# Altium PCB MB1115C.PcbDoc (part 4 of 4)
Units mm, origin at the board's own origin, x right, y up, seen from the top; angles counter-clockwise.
Board outline 66 x 97 mm, 2 copper layers (TOP, Bottom), stack 1.535 mm thick; 198 components, 186 nets, 760 pads, 493 vias.

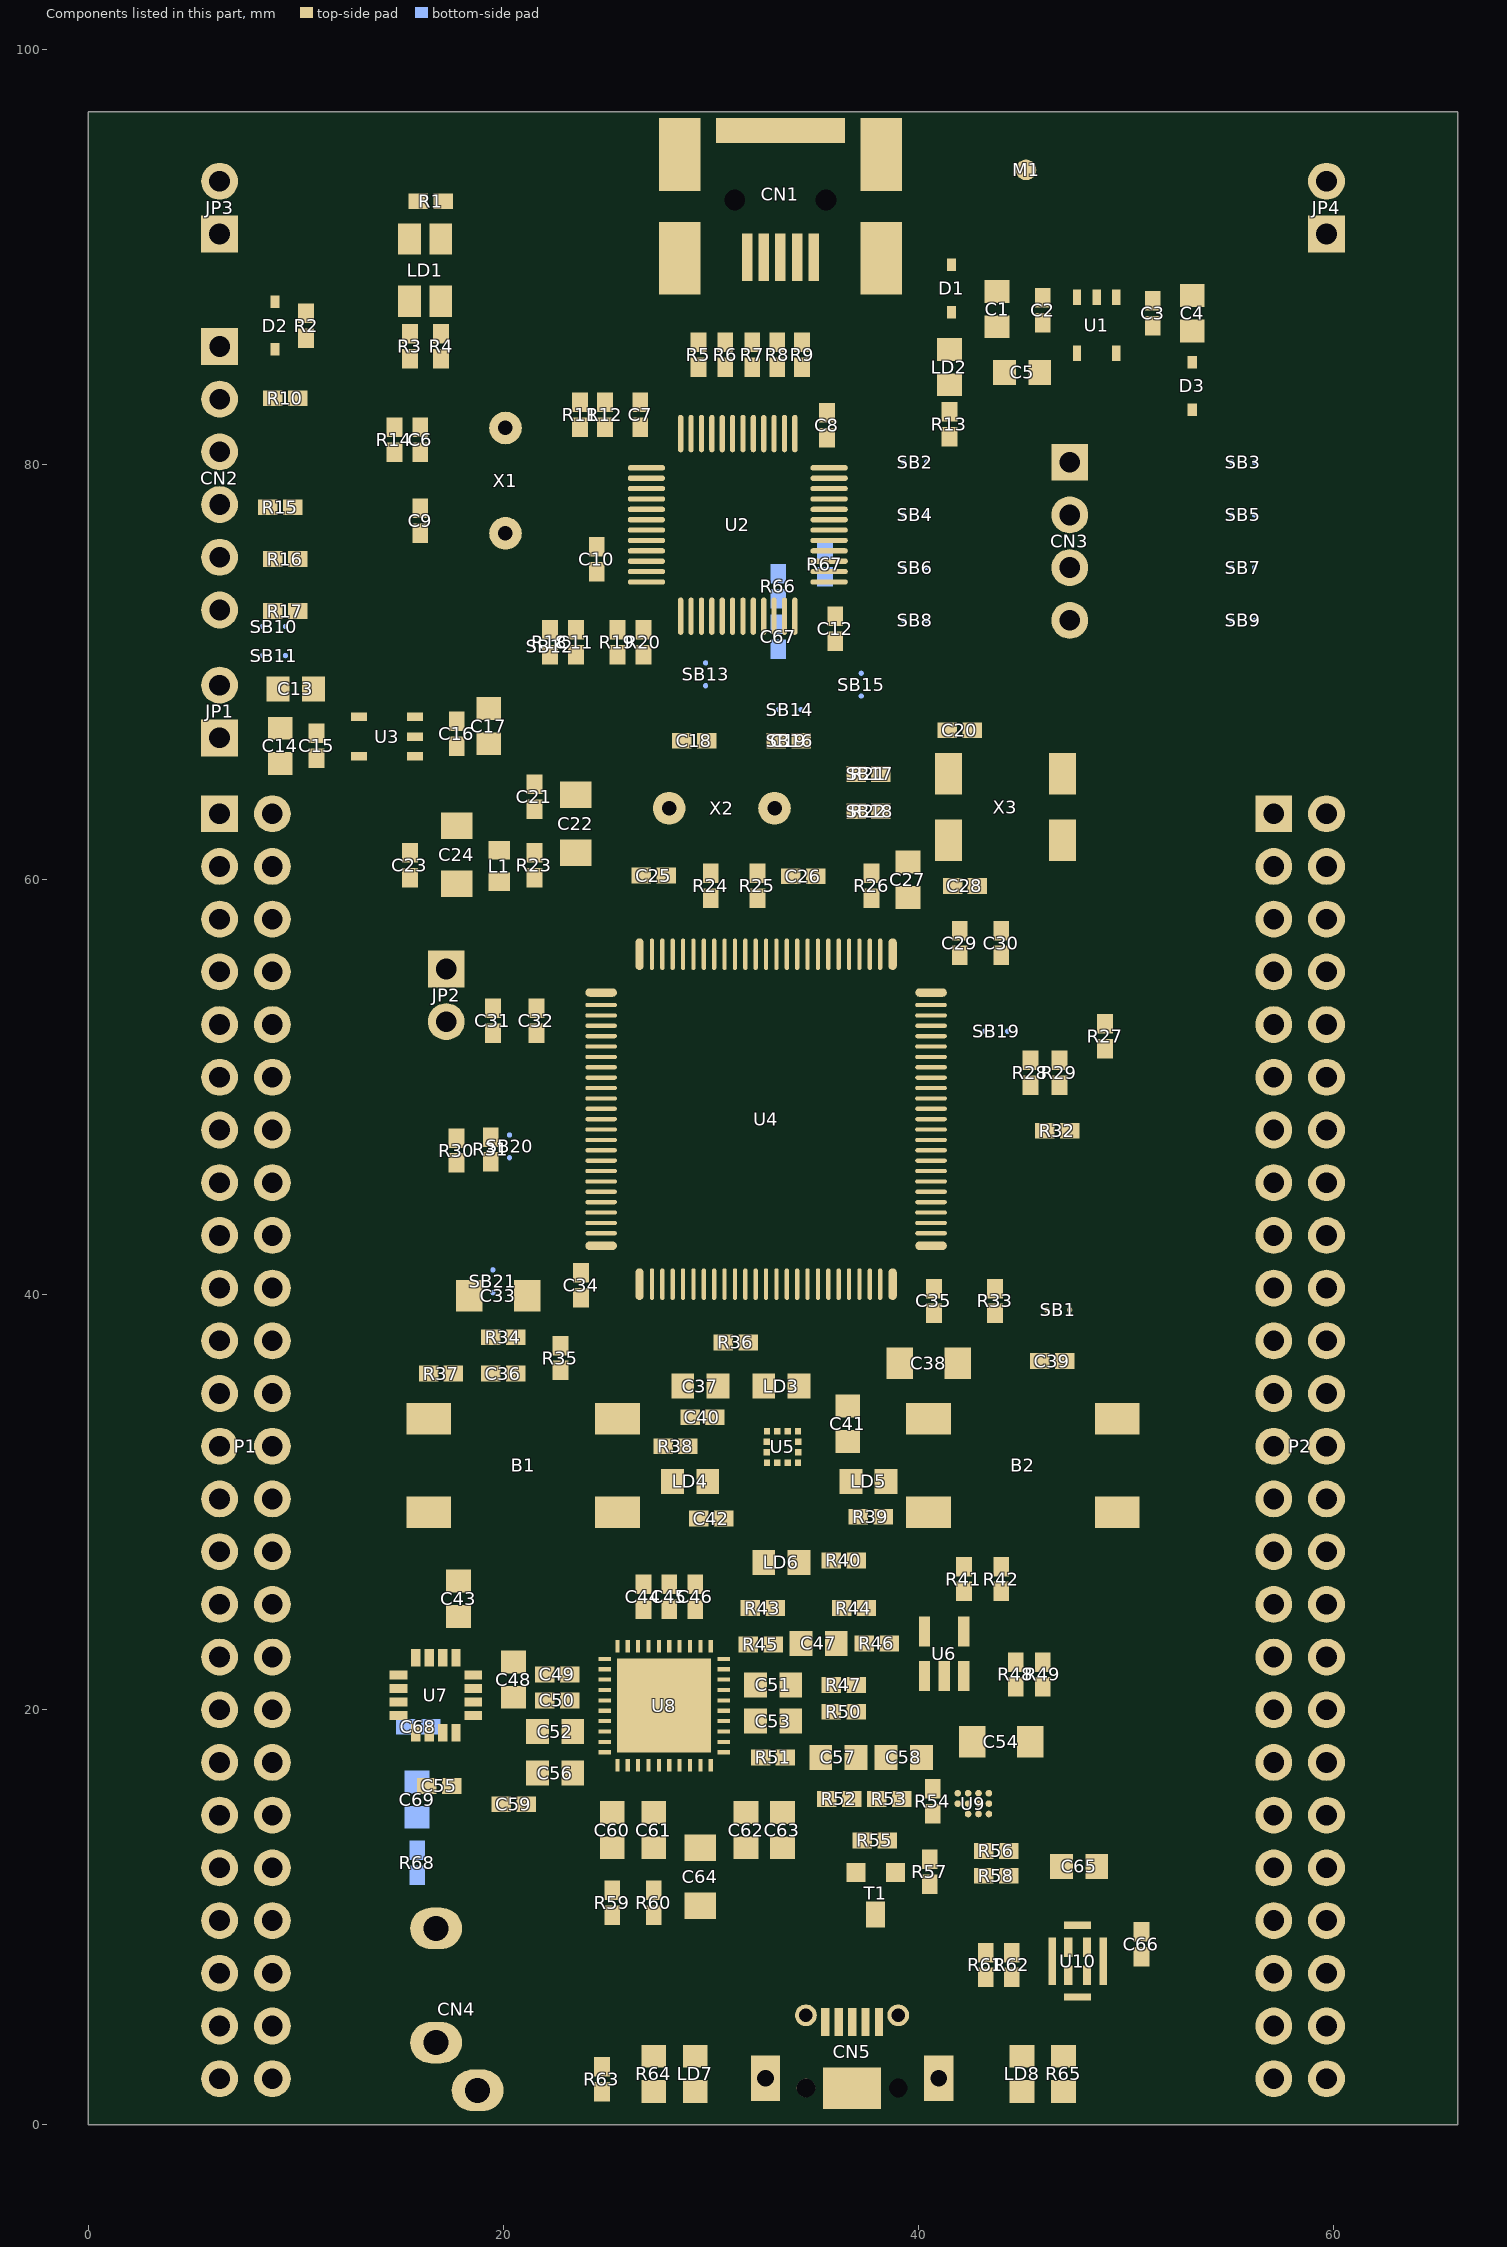
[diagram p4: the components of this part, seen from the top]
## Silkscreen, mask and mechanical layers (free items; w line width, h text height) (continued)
CARTOUCHE FX:
  region: -36.803,-105.755 -42.634,-105.752 -42.899,-105.221 -40.613,-102.935 -40.308,-102.249 -40.308,-101.411 -40.385,-101.106 -40.689,-100.573 -40.994,-100.268 -41.375,-100.04 -41.832,-99.887 -42.366,-99.811 -53.186,-99.811 -52.577,-101.411 -52.5,-101.487 -49.986,-101.487 -47.547,-107.279 -45.795,-107.279 -48.157,-101.716 -48.157,-101.487 -42.137,-101.487 -41.985,-101.564 -41.909,-101.716 -41.909,-101.945 -41.985,-102.021 -44.195,-104.154 -44.423,-104.535 -44.499,-104.916 -44.576,-104.993 -44.576,-105.678 ccw(c-42.303,-105.211) -43.356,-107.279 -36.194,-107.279 -36.194,-107.126 -36.727,-105.831
  lines w0.203: -23.15,-115.18 86.07,-115.18 ; -23.15,-106.29 86.07,-106.29 ; -53.643,-98.82 -53.643,-98.516 -53.567,-98.439 -40.918,-98.439 cw(c-41.412,-100.811) -39.242,-99.735 -36.194,-107.126 -36.194,-107.279 -36.346,-107.431 -48.919,-107.431 cw(c-48.354,-104.967) -50.595,-106.136 -53.643,-98.82
  lines w0.508: -67.6,-82.16 122.9,-82.16 122.9,-122.8 ; 89.88,-107.56 120.36,-107.56 ; 89.88,-96.13 120.36,-96.13 ; -67.6,-122.8 -67.6,164.2 132.4,164.2 132.4,-122.8 -67.6,-122.8 ; -65.06,-120.26 -65.06,-84.7 -26.96,-84.7 -26.96,-120.26 -65.06,-120.26 ; -24.42,-120.26 87.34,-120.26 87.34,-97.4 -24.42,-97.4 -24.42,-120.26 ; -24.42,-94.86 87.34,-94.86 87.34,-84.7 -24.42,-84.7 -24.42,-94.86 ; 89.88,-120.26 120.36,-120.26 120.36,-84.7 89.88,-84.7 89.88,-120.26
  text "DATE:" at 118.777,-89.825 h1.78
  text "10/07/2013" at 118.777,-93.825 h1.5
  text "STM32F401C-DISCOVERY" at 84.9,-105.3 h2.45
  text "MB1115B" at 84.9,-114.3 h2.45
  text "S.M.E.E." at 116.867,-117.185 h3.5

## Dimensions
57.13,2.22 to 59.67,2.22 on MECHANICAL DRAWING
59.67,2.22 to 66,0 on MECHANICAL DRAWING
6.33,2.22 to 8.87,2.22 on User Attributes
6.33,2.22 to 0,0 on MECHANICAL DRAWING
0,97 to 0,0 on MECHANICAL DRAWING
66,97 to 66,0 on MECHANICAL DRAWING
6.33,93.66 to 0,97 on MECHANICAL DRAWING
0,0 to 6.33,2.22 on MECHANICAL DRAWING
59.67,93.66 to 66,97 on MECHANICAL DRAWING
6.33,63.18 to 6.33,93.66 on MECHANICAL DRAWING
6.33,2.22 to 0,0 on User Attributes
59.67,93.66 to 59.67,63.18 on MECHANICAL DRAWING
0,97 to 66,97 on MECHANICAL DRAWING
6.33,93.66 to 0,97 on MECHANICAL DRAWING
6.33,2.22 to 59.67,2.22 on MECHANICAL DRAWING
0,0 to 66,0 on User Attributes
6.33,2.22 to 59.67,2.22 on User Attributes
59.67,2.22 to 66,0.7 on User Attributes
59.67,2.22 to 66,0 on User Attributes
66,0 to 59.67,2.22 on MECHANICAL DRAWING
59.67,2.22 to 57.13,2.22 on User Attributes
59.67,63.18 to 66,97 on User Attributes
59.67,93.66 to 66,97 on MECHANICAL DRAWING
8.87,2.22 to 6.33,2.22 on MECHANICAL DRAWING
6.33,91.12 to 6.33,63.18 on User Attributes
59.67,91.12 to 59.67,63.18 on User Attributes
6.33,2.22 to 0,0 on User Attributes
6.33,93.66 to 59.67,93.66 on User Attributes
0,97 to 66,97 on User Attributes
6.33,93.66 to 0,97 on User Attributes
6.33,93.66 to 0,97 on User Attributes
66,97 to 59.67,93.66 on User Attributes
59.67,93.66 to 66,97 on User Attributes
0,97 to 0,0 on User Attributes
6.33,63.18 to 6.33,2.22 on User Attributes
59.67,63.18 to 59.67,2.22 on User Attributes
0,97 to 6.33,63.18 on User Attributes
